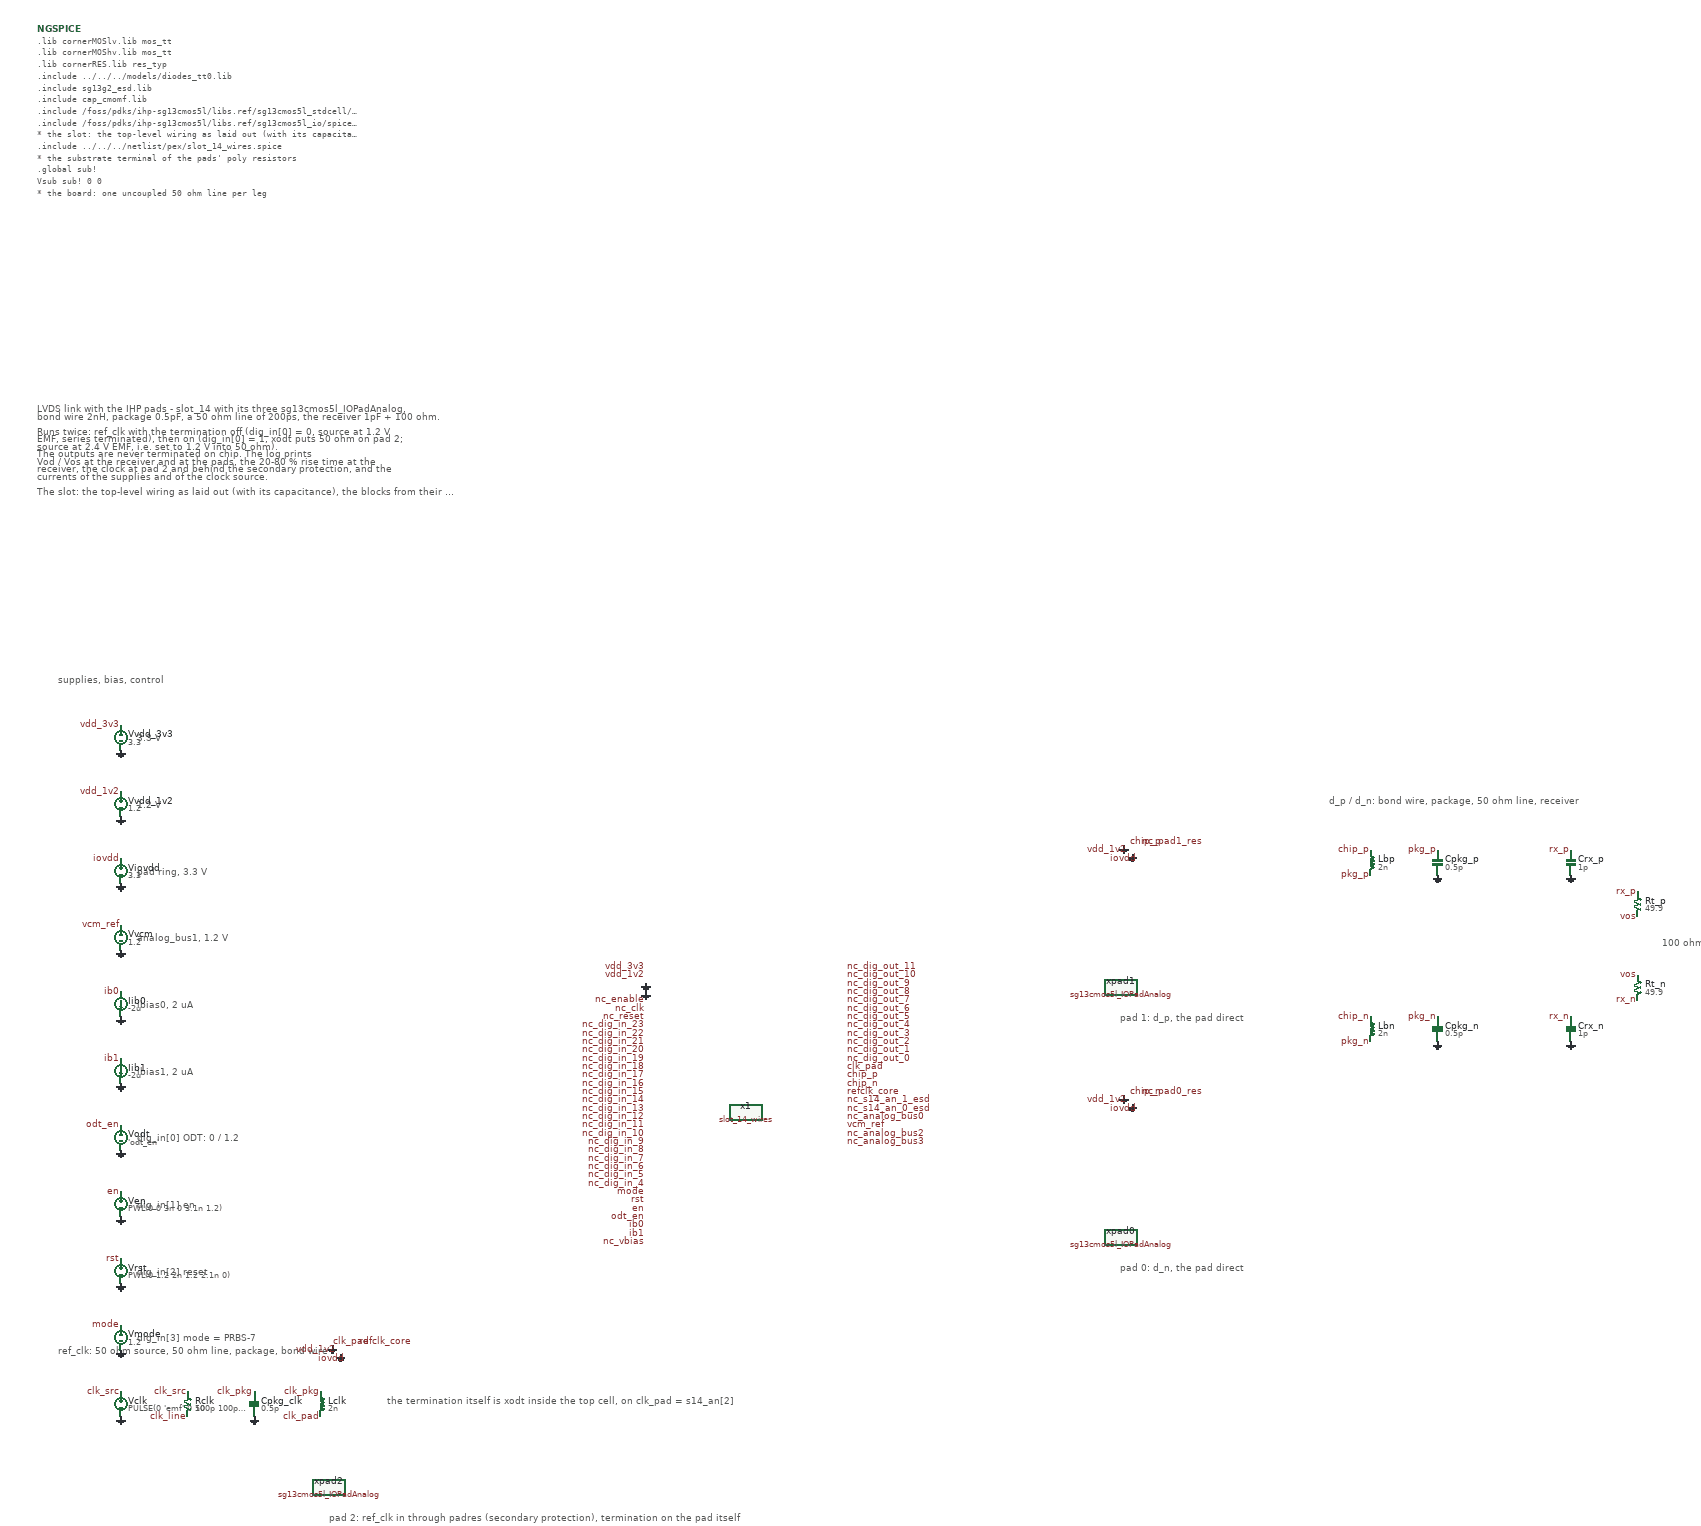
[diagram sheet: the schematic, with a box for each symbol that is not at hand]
v {xschem version=3.4.8RC file_version=1.3}
G {}
K {}
V {}
S {}
F {}
E {}
C {slot_14_wires.sym} 0 0 0 0 {name=x1}
C {devices/lab_pin.sym} -240 -350 0 0 {name=p1 sig_type=std_logic lab=vdd_3v3}
C {devices/lab_pin.sym} -240 -330 0 0 {name=p2 sig_type=std_logic lab=vdd_1v2}
C {devices/gnd.sym} -240 -310 1 0 {name=g3 lab=GND}
C {devices/gnd.sym} -240 -290 1 0 {name=g4 lab=GND}
C {devices/lab_pin.sym} -240 -270 0 0 {name=p5 sig_type=std_logic lab=nc_enable}
C {devices/lab_pin.sym} -240 -250 0 0 {name=p6 sig_type=std_logic lab=nc_clk}
C {devices/lab_pin.sym} -240 -230 0 0 {name=p7 sig_type=std_logic lab=nc_reset}
C {devices/lab_pin.sym} -240 -210 0 0 {name=p8 sig_type=std_logic lab=nc_dig_in_23}
C {devices/lab_pin.sym} -240 -190 0 0 {name=p9 sig_type=std_logic lab=nc_dig_in_22}
C {devices/lab_pin.sym} -240 -170 0 0 {name=p10 sig_type=std_logic lab=nc_dig_in_21}
C {devices/lab_pin.sym} -240 -150 0 0 {name=p11 sig_type=std_logic lab=nc_dig_in_20}
C {devices/lab_pin.sym} -240 -130 0 0 {name=p12 sig_type=std_logic lab=nc_dig_in_19}
C {devices/lab_pin.sym} -240 -110 0 0 {name=p13 sig_type=std_logic lab=nc_dig_in_18}
C {devices/lab_pin.sym} -240 -90 0 0 {name=p14 sig_type=std_logic lab=nc_dig_in_17}
C {devices/lab_pin.sym} -240 -70 0 0 {name=p15 sig_type=std_logic lab=nc_dig_in_16}
C {devices/lab_pin.sym} -240 -50 0 0 {name=p16 sig_type=std_logic lab=nc_dig_in_15}
C {devices/lab_pin.sym} -240 -30 0 0 {name=p17 sig_type=std_logic lab=nc_dig_in_14}
C {devices/lab_pin.sym} -240 -10 0 0 {name=p18 sig_type=std_logic lab=nc_dig_in_13}
C {devices/lab_pin.sym} -240 10 0 0 {name=p19 sig_type=std_logic lab=nc_dig_in_12}
C {devices/lab_pin.sym} -240 30 0 0 {name=p20 sig_type=std_logic lab=nc_dig_in_11}
C {devices/lab_pin.sym} -240 50 0 0 {name=p21 sig_type=std_logic lab=nc_dig_in_10}
C {devices/lab_pin.sym} -240 70 0 0 {name=p22 sig_type=std_logic lab=nc_dig_in_9}
C {devices/lab_pin.sym} -240 90 0 0 {name=p23 sig_type=std_logic lab=nc_dig_in_8}
C {devices/lab_pin.sym} -240 110 0 0 {name=p24 sig_type=std_logic lab=nc_dig_in_7}
C {devices/lab_pin.sym} -240 130 0 0 {name=p25 sig_type=std_logic lab=nc_dig_in_6}
C {devices/lab_pin.sym} -240 150 0 0 {name=p26 sig_type=std_logic lab=nc_dig_in_5}
C {devices/lab_pin.sym} -240 170 0 0 {name=p27 sig_type=std_logic lab=nc_dig_in_4}
C {devices/lab_pin.sym} -240 190 0 0 {name=p28 sig_type=std_logic lab=mode}
C {devices/lab_pin.sym} -240 210 0 0 {name=p29 sig_type=std_logic lab=rst}
C {devices/lab_pin.sym} -240 230 0 0 {name=p30 sig_type=std_logic lab=en}
C {devices/lab_pin.sym} -240 250 0 0 {name=p31 sig_type=std_logic lab=odt_en}
C {devices/lab_pin.sym} -240 270 0 0 {name=p32 sig_type=std_logic lab=ib0}
C {devices/lab_pin.sym} -240 290 0 0 {name=p33 sig_type=std_logic lab=ib1}
C {devices/lab_pin.sym} -240 310 0 0 {name=p34 sig_type=std_logic lab=nc_vbias}
C {devices/lab_pin.sym} 240 -350 0 1 {name=p35 sig_type=std_logic lab=nc_dig_out_11}
C {devices/lab_pin.sym} 240 -330 0 1 {name=p36 sig_type=std_logic lab=nc_dig_out_10}
C {devices/lab_pin.sym} 240 -310 0 1 {name=p37 sig_type=std_logic lab=nc_dig_out_9}
C {devices/lab_pin.sym} 240 -290 0 1 {name=p38 sig_type=std_logic lab=nc_dig_out_8}
C {devices/lab_pin.sym} 240 -270 0 1 {name=p39 sig_type=std_logic lab=nc_dig_out_7}
C {devices/lab_pin.sym} 240 -250 0 1 {name=p40 sig_type=std_logic lab=nc_dig_out_6}
C {devices/lab_pin.sym} 240 -230 0 1 {name=p41 sig_type=std_logic lab=nc_dig_out_5}
C {devices/lab_pin.sym} 240 -210 0 1 {name=p42 sig_type=std_logic lab=nc_dig_out_4}
C {devices/lab_pin.sym} 240 -190 0 1 {name=p43 sig_type=std_logic lab=nc_dig_out_3}
C {devices/lab_pin.sym} 240 -170 0 1 {name=p44 sig_type=std_logic lab=nc_dig_out_2}
C {devices/lab_pin.sym} 240 -150 0 1 {name=p45 sig_type=std_logic lab=nc_dig_out_1}
C {devices/lab_pin.sym} 240 -130 0 1 {name=p46 sig_type=std_logic lab=nc_dig_out_0}
C {devices/lab_pin.sym} 240 -110 0 1 {name=p47 sig_type=std_logic lab=clk_pad}
C {devices/lab_pin.sym} 240 -90 0 1 {name=p48 sig_type=std_logic lab=chip_p}
C {devices/lab_pin.sym} 240 -70 0 1 {name=p49 sig_type=std_logic lab=chip_n}
C {devices/lab_pin.sym} 240 -50 0 1 {name=p50 sig_type=std_logic lab=refclk_core}
C {devices/lab_pin.sym} 240 -30 0 1 {name=p51 sig_type=std_logic lab=nc_s14_an_1_esd}
C {devices/lab_pin.sym} 240 -10 0 1 {name=p52 sig_type=std_logic lab=nc_s14_an_0_esd}
C {devices/lab_pin.sym} 240 10 0 1 {name=p53 sig_type=std_logic lab=nc_analog_bus0}
C {devices/lab_pin.sym} 240 30 0 1 {name=p54 sig_type=std_logic lab=vcm_ref}
C {devices/lab_pin.sym} 240 50 0 1 {name=p55 sig_type=std_logic lab=nc_analog_bus2}
C {devices/lab_pin.sym} 240 70 0 1 {name=p56 sig_type=std_logic lab=nc_analog_bus3}
T {supplies, bias, control} -1650 -1050 0 0 0.4 0.4 {}
C {devices/vsource.sym} -1500 -900 0 0 {name=Vvdd_3v3 value="3.3"}
C {devices/lab_pin.sym} -1500 -930 0 0 {name=p57 sig_type=std_logic lab=vdd_3v3}
C {devices/gnd.sym} -1500 -870 0 0 {name=g58 lab=GND}
T {3.3 V} -1460 -910 0 0 0.3 0.3 {}
C {devices/vsource.sym} -1500 -740 0 0 {name=Vvdd_1v2 value="1.2"}
C {devices/lab_pin.sym} -1500 -770 0 0 {name=p59 sig_type=std_logic lab=vdd_1v2}
C {devices/gnd.sym} -1500 -710 0 0 {name=g60 lab=GND}
T {1.2 V} -1460 -750 0 0 0.3 0.3 {}
C {devices/vsource.sym} -1500 -580 0 0 {name=Viovdd value="3.3"}
C {devices/lab_pin.sym} -1500 -610 0 0 {name=p61 sig_type=std_logic lab=iovdd}
C {devices/gnd.sym} -1500 -550 0 0 {name=g62 lab=GND}
T {pad ring, 3.3 V} -1460 -590 0 0 0.3 0.3 {}
C {devices/vsource.sym} -1500 -420 0 0 {name=Vvcm value="1.2"}
C {devices/lab_pin.sym} -1500 -450 0 0 {name=p63 sig_type=std_logic lab=vcm_ref}
C {devices/gnd.sym} -1500 -390 0 0 {name=g64 lab=GND}
T {analog_bus1, 1.2 V} -1460 -430 0 0 0.3 0.3 {}
C {isource.sym} -1500 -260 0 0 {name=Iib0 value="-2u"}
C {devices/lab_pin.sym} -1500 -290 0 0 {name=p65 sig_type=std_logic lab=ib0}
C {devices/gnd.sym} -1500 -230 0 0 {name=g66 lab=GND}
T {ibias0, 2 uA} -1460 -270 0 0 0.3 0.3 {}
C {isource.sym} -1500 -100 0 0 {name=Iib1 value="-2u"}
C {devices/lab_pin.sym} -1500 -130 0 0 {name=p67 sig_type=std_logic lab=ib1}
C {devices/gnd.sym} -1500 -70 0 0 {name=g68 lab=GND}
T {ibias1, 2 uA} -1460 -110 0 0 0.3 0.3 {}
C {devices/vsource.sym} -1500 60 0 0 {name=Vodt value="'odt_en'"}
C {devices/lab_pin.sym} -1500 30 0 0 {name=p69 sig_type=std_logic lab=odt_en}
C {devices/gnd.sym} -1500 90 0 0 {name=g70 lab=GND}
T {dig_in[0] ODT: 0 / 1.2} -1460 50 0 0 0.3 0.3 {}
C {devices/vsource.sym} -1500 220 0 0 {name=Ven value="PWL(0 0 3n 0 3.1n 1.2)"}
C {devices/lab_pin.sym} -1500 190 0 0 {name=p71 sig_type=std_logic lab=en}
C {devices/gnd.sym} -1500 250 0 0 {name=g72 lab=GND}
T {dig_in[1] en} -1460 210 0 0 0.3 0.3 {}
C {devices/vsource.sym} -1500 380 0 0 {name=Vrst value="PWL(0 1.2 2n 1.2 2.1n 0)"}
C {devices/lab_pin.sym} -1500 350 0 0 {name=p73 sig_type=std_logic lab=rst}
C {devices/gnd.sym} -1500 410 0 0 {name=g74 lab=GND}
T {dig_in[2] reset} -1460 370 0 0 0.3 0.3 {}
C {devices/vsource.sym} -1500 540 0 0 {name=Vmode value="1.2"}
C {devices/lab_pin.sym} -1500 510 0 0 {name=p75 sig_type=std_logic lab=mode}
C {devices/gnd.sym} -1500 570 0 0 {name=g76 lab=GND}
T {dig_in[3] mode = PRBS-7} -1460 530 0 0 0.3 0.3 {}
C {sg13cmos5l_io/sg13cmos5l_IOPadAnalog.sym} -1000 900 0 0 {name=xpad2}
C {devices/gnd.sym} -992.5 560 0 0 {name=g77 lab=GND}
C {devices/lab_pin.sym} -982.5 570 0 0 {name=p78 sig_type=std_logic lab=vdd_1v2}
C {devices/gnd.sym} -972.5 580 0 0 {name=g79 lab=GND}
C {devices/lab_pin.sym} -960 590 0 0 {name=p80 sig_type=std_logic lab=iovdd}
C {devices/lab_pin.sym} -900 550 0 0 {name=p81 sig_type=std_logic lab=clk_pad}
C {devices/lab_pin.sym} -800 550 0 0 {name=p82 sig_type=std_logic lab=refclk_core}
C {sg13cmos5l_io/sg13cmos5l_IOPadAnalog.sym} 900 -300 0 0 {name=xpad1}
C {devices/gnd.sym} 907.5 -640 0 0 {name=g83 lab=GND}
C {devices/lab_pin.sym} 917.5 -630 0 0 {name=p84 sig_type=std_logic lab=vdd_1v2}
C {devices/gnd.sym} 927.5 -620 0 0 {name=g85 lab=GND}
C {devices/lab_pin.sym} 940 -610 0 0 {name=p86 sig_type=std_logic lab=iovdd}
C {devices/lab_pin.sym} 1000 -650 0 0 {name=p87 sig_type=std_logic lab=chip_p}
C {devices/lab_pin.sym} 1100 -650 0 0 {name=p88 sig_type=std_logic lab=nc_pad1_res}
C {sg13cmos5l_io/sg13cmos5l_IOPadAnalog.sym} 900 300 0 0 {name=xpad0}
C {devices/gnd.sym} 907.5 -40 0 0 {name=g89 lab=GND}
C {devices/lab_pin.sym} 917.5 -30 0 0 {name=p90 sig_type=std_logic lab=vdd_1v2}
C {devices/gnd.sym} 927.5 -20 0 0 {name=g91 lab=GND}
C {devices/lab_pin.sym} 940 -10 0 0 {name=p92 sig_type=std_logic lab=iovdd}
C {devices/lab_pin.sym} 1000 -50 0 0 {name=p93 sig_type=std_logic lab=chip_n}
C {devices/lab_pin.sym} 1100 -50 0 0 {name=p94 sig_type=std_logic lab=nc_pad0_res}
T {pad 2: ref_clk in through padres (secondary protection), termination on the pad itself} -1000 960 0 0 0.3 0.3 {}
T {pad 1: d_p, the pad direct} 900 -240 0 0 0.3 0.3 {}
T {pad 0: d_n, the pad direct} 900 360 0 0 0.3 0.3 {}
T {ref_clk: 50 ohm source, 50 ohm line, package, bond wire} -1650 560 0 0 0.35 0.35 {}
C {devices/vsource.sym} -1500 700 0 0 {name=Vclk value="PULSE(0 'emf' 0 100p 100p 0.9n 2n)"}
C {devices/lab_pin.sym} -1500 670 0 0 {name=p95 sig_type=std_logic lab=clk_src}
C {devices/gnd.sym} -1500 730 0 0 {name=g96 lab=GND}
C {res.sym} -1340 700 0 0 {name=Rclk value="50"}
C {devices/lab_pin.sym} -1340 670 0 0 {name=p97 sig_type=std_logic lab=clk_src}
C {devices/lab_pin.sym} -1340 730 0 0 {name=p98 sig_type=std_logic lab=clk_line}
C {capa.sym} -1180 700 0 0 {name=Cpkg_clk value="0.5p"}
C {devices/lab_pin.sym} -1180 670 0 0 {name=p99 sig_type=std_logic lab=clk_pkg}
C {devices/gnd.sym} -1180 730 0 0 {name=g100 lab=GND}
C {ind.sym} -1020 700 0 0 {name=Lclk value="2n"}
C {devices/lab_pin.sym} -1020 670 0 0 {name=p101 sig_type=std_logic lab=clk_pkg}
C {devices/lab_pin.sym} -1020 730 0 0 {name=p102 sig_type=std_logic lab=clk_pad}
T {the termination itself is xodt inside the top cell, on clk_pad = s14_an[2]} -860 680 0 0 0.3 0.3 {}
T {d_p / d_n: bond wire, package, 50 ohm line, receiver} 1400 -760 0 0 0.35 0.35 {}
C {ind.sym} 1500 -600 0 0 {name=Lbp value="2n"}
C {devices/lab_pin.sym} 1500 -630 0 0 {name=p103 sig_type=std_logic lab=chip_p}
C {devices/lab_pin.sym} 1500 -570 0 0 {name=p104 sig_type=std_logic lab=pkg_p}
C {capa.sym} 1660 -600 0 0 {name=Cpkg_p value="0.5p"}
C {devices/lab_pin.sym} 1660 -630 0 0 {name=p105 sig_type=std_logic lab=pkg_p}
C {devices/gnd.sym} 1660 -570 0 0 {name=g106 lab=GND}
C {capa.sym} 1980 -600 0 0 {name=Crx_p value="1p"}
C {devices/lab_pin.sym} 1980 -630 0 0 {name=p107 sig_type=std_logic lab=rx_p}
C {devices/gnd.sym} 1980 -570 0 0 {name=g108 lab=GND}
C {ind.sym} 1500 -200 0 0 {name=Lbn value="2n"}
C {devices/lab_pin.sym} 1500 -230 0 0 {name=p109 sig_type=std_logic lab=chip_n}
C {devices/lab_pin.sym} 1500 -170 0 0 {name=p110 sig_type=std_logic lab=pkg_n}
C {capa.sym} 1660 -200 0 0 {name=Cpkg_n value="0.5p"}
C {devices/lab_pin.sym} 1660 -230 0 0 {name=p111 sig_type=std_logic lab=pkg_n}
C {devices/gnd.sym} 1660 -170 0 0 {name=g112 lab=GND}
C {capa.sym} 1980 -200 0 0 {name=Crx_n value="1p"}
C {devices/lab_pin.sym} 1980 -230 0 0 {name=p113 sig_type=std_logic lab=rx_n}
C {devices/gnd.sym} 1980 -170 0 0 {name=g114 lab=GND}
C {res.sym} 2140 -500 0 0 {name=Rt_p value="49.9"}
C {devices/lab_pin.sym} 2140 -530 0 0 {name=p115 sig_type=std_logic lab=rx_p}
C {devices/lab_pin.sym} 2140 -470 0 0 {name=p116 sig_type=std_logic lab=vos}
C {res.sym} 2140 -300 0 0 {name=Rt_n value="49.9"}
C {devices/lab_pin.sym} 2140 -330 0 0 {name=p117 sig_type=std_logic lab=vos}
C {devices/lab_pin.sym} 2140 -270 0 0 {name=p118 sig_type=std_logic lab=rx_n}
T {100 ohm at the receiver, mid-point = Vos} 2200 -420 0 0 0.3 0.3 {}
T {LVDS link with the IHP pads - slot_14 with its three sg13cmos5l_IOPadAnalog,
bond wire 2nH, package 0.5pF, a 50 ohm line of 200ps, the receiver 1pF + 100 ohm.

Runs twice: ref_clk with the termination off (dig_in[0] = 0, source at 1.2 V
EMF, series terminated), then on (dig_in[0] = 1, xodt puts 50 ohm on pad 2;
source at 2.4 V EMF, i.e. set to 1.2 V into 50 ohm).
The outputs are never terminated on chip.  The log prints
Vod / Vos at the receiver and at the pads, the 20-80 % rise time at the
receiver, the clock at pad 2 and behind the secondary protection, and the
currents of the supplies and of the clock source.

The slot: the top-level wiring as laid out (with its capacitance), the blocks from their schematics
(slot_14_wires.spice, from scripts/sim/extract_top.sh - run make extract-top after a layout change).
The pad cells are the PDK's spice model.  The schematic without pads: slot_14_tb_lvds.} -1700 -1700 0 0 0.45 0.45 {}
C {devices/code_shown.sym} -1700 -2600 0 0 {name=NGSPICE
only_toplevel=true
value="
.lib cornerMOSlv.lib mos_tt
.lib cornerMOShv.lib mos_tt
.lib cornerRES.lib res_typ
.include ../../../models/diodes_tt0.lib
.include sg13g2_esd.lib
.include cap_cmomf.lib
.include /foss/pdks/ihp-sg13cmos5l/libs.ref/sg13cmos5l_stdcell/spice/sg13cmos5l_stdcell.spice
.include /foss/pdks/ihp-sg13cmos5l/libs.ref/sg13cmos5l_io/spice/sg13cmos5l_io.spi
* the slot: the top-level wiring as laid out (with its capacitance), the blocks from their schematics
.include ../../../netlist/pex/slot_14_wires.spice
* the substrate terminal of the pads' poly resistors
.global sub!
Vsub sub! 0 0
* the board: one uncoupled 50 ohm line per leg
Tclk clk_line 0 clk_pkg 0 Z0=50 TD=200p
Tp pkg_p 0 rx_p 0 Z0=50 TD=200p
Tn pkg_n 0 rx_n 0 Z0=50 TD=200p
.param odt_en=0 emf=1.2
.temp 27
.options savecurrents klu method=trap reltol=1e-3 abstol=1e-12 gmin=1e-12
.ic v(x1.xlvds.xdrv.cmfb)=1.54
.control
save rx_p rx_n vos chip_p chip_n refclk_core clk_pad x1.core_p x1.core_n i(Vvdd_3v3) i(Vvdd_1v2) i(Viovdd) i(Vclk)
* 1 = ODT off only, 2 = then once more with the termination on
let runs = 2
let run = 0
while run < runs
  if run = 1
    alterparam odt_en=1.2
    alterparam emf=2.4
    reset
  end
  tran 5p 300n 0 5p
  let vd = v(rx_p)-v(rx_n)
  let vdpad = v(chip_p)-v(chip_n)
  meas tran vod_max MAX vd from=120n to=295n
  meas tran vod_min MIN vd from=120n to=295n
  meas tran vos_avg AVG v(vos) from=120n to=295n
  meas tran vos_max MAX v(vos) from=120n to=295n
  meas tran vos_min MIN v(vos) from=120n to=295n
  let vos_pp = vos_max - vos_min
  meas tran vodpad_max MAX vdpad from=120n to=295n
  meas tran vodpad_min MIN vdpad from=120n to=295n
  let th20 = vod_min + 0.2*(vod_max - vod_min)
  let th80 = vod_min + 0.8*(vod_max - vod_min)
  meas tran t20 WHEN vd=$&th20 RISE=5 FROM=150n
  meas tran t80 WHEN vd=$&th80 RISE=5 FROM=150n
  let trise = t80 - t20
  meas tran ck_max MAX v(refclk_core) from=120n to=295n
  meas tran ck_min MIN v(refclk_core) from=120n to=295n
  meas tran pad_max MAX v(clk_pad) from=120n to=295n
  meas tran pad_min MIN v(clk_pad) from=120n to=295n
  meas tran i_clk AVG i(Vclk) from=120n to=295n
* the pattern pair between lvds_pattern and lvds_tx: a static pair means the
* clock or the control never arrived, and the numbers above mean nothing
  meas tran core_pp PP v(x1.core_p) from=120n to=295n
  meas tran i_3v3 AVG i(Vvdd_3v3) from=120n to=295n
  meas tran i_1v2 AVG i(Vvdd_1v2) from=120n to=295n
  meas tran i_io AVG i(Viovdd) from=120n to=295n
  echo === run $&run - 0 dig_in 0 = 0 ODT off, 1 dig_in 0 = 1 ODT on
  print vod_max vod_min vos_avg vos_pp vodpad_max vodpad_min trise
  print ck_max ck_min pad_max pad_min core_pp i_3v3 i_1v2 i_io i_clk
  set wr_vecnames
  set wr_singlescale
  if run = 0
    wrdata ../plot_simulations/data/@schname\\\\_noodt.txt vd vdpad v(vos) v(refclk_core) v(clk_pad)
  else
    wrdata ../plot_simulations/data/@schname\\\\_odt.txt vd vdpad v(vos) v(refclk_core) v(clk_pad)
  end
  let run = run + 1
end
.endc
"}
